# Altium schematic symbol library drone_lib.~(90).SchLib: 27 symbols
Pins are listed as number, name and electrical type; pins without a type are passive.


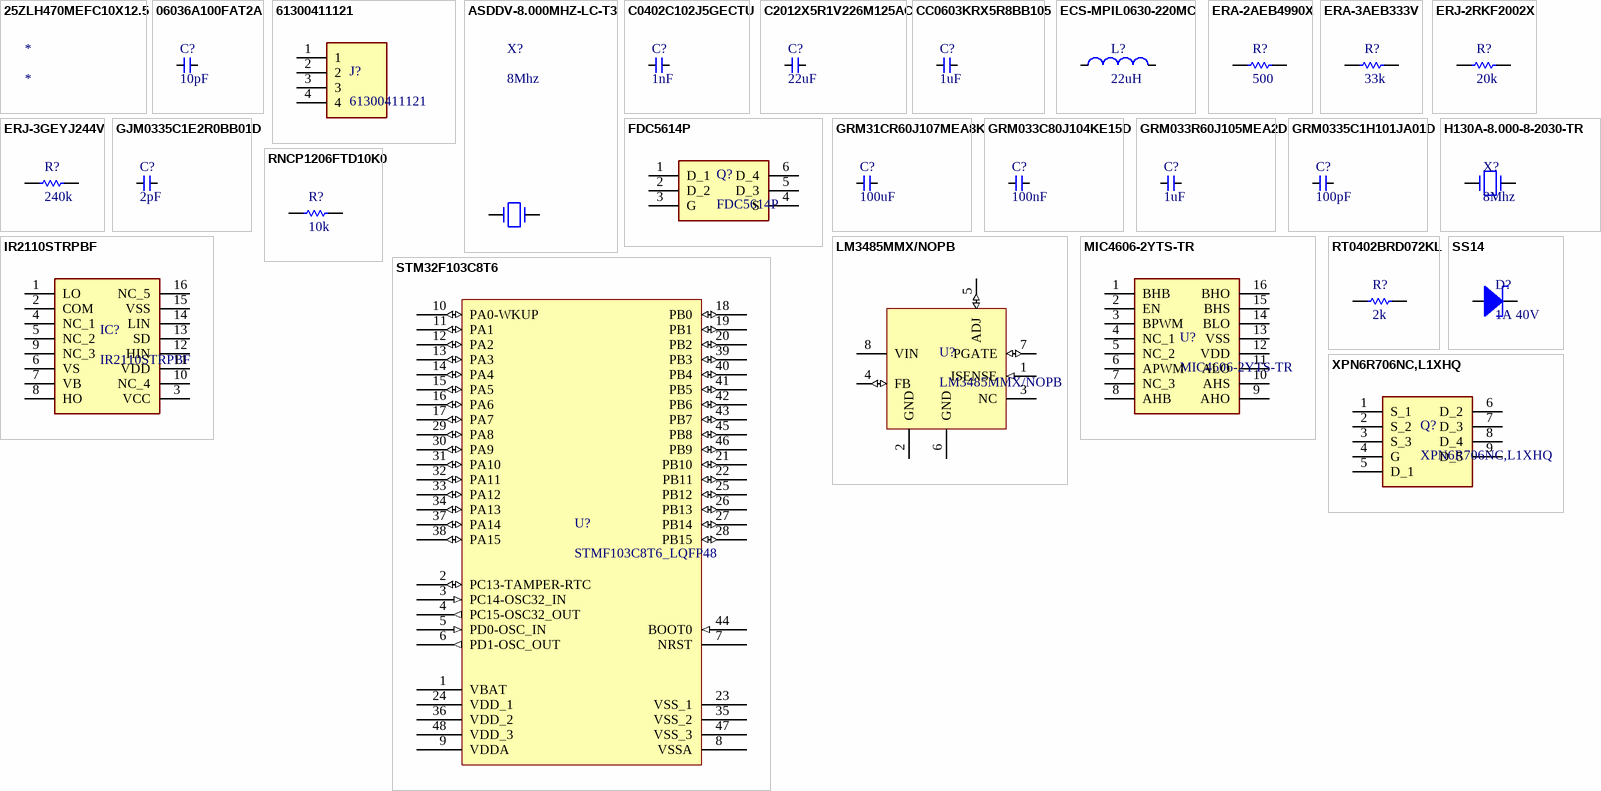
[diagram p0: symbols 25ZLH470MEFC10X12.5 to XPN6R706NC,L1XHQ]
## 25ZLH470MEFC10X12.5
designator *
Aluminum Electrolytic Capacitor, Polarized, Aluminum (wet), 25V, 20% +Tol, 20% -Tol, 470uF, Through Hole Mount; Manufacturer: Rubycon; Manufacturer Part Number: 25ZLH470MEFC10X12.5; Dielectric Material: Aluminium; Leakage Current: 117.5uA; Ripple Current: 731.5mA; Tan Delta: 0.14

## 06036A100FAT2A
designator C?, comment 10pF
Ceramic Capacitor, Ceramic, 6.3V, 1% +Tol, 1% -Tol, C0G, -/+30ppm/Cel TC, 0.00001uF, Surface Mount, 0603; Manufacturer: Kyocera AVX; Manufacturer Part Number: 06036A100FAT2A; Multilayer: No
pins: 1, 2

## 61300411121
designator J?
pins: 1, 2, 3, 4

## ASDDV-8.000MHZ-LC-T3
designator X?, comment 8Mhz
Osc, 8MHZ, Cmos/hcmos/lvcmos, SMD Rohs Compliant: Yes; Manufacturer: Abracon; Manufacturer Part Number: ASDDV-8.000MHZ-LC-T3
pins: 1, 2

## C0402C102J5GECTU
designator C?, comment 1nF
Ceramic Capacitor, Multilayer, Ceramic, 50V, 5% +Tol, 5% -Tol, C0G, -/+30ppm/Cel TC, 0.001uF, Surface Mount, 0402; Manufacturer: KEMET; Manufacturer Part Number: C0402C102J5GECTU
footprint C0402C104J4RACTU
pins: 1, 2

## C2012X5R1V226M125AC
designator C?, comment 22uF
Ceramic Capacitor, Multilayer, Ceramic, 35V, 20% +Tol, 20% -Tol, X5R, 15% TC, 22uF, Surface Mount, 0805; Manufacturer: TDK; Manufacturer Part Number: C2012X5R1V226M125AC; Multilayer: Yes
footprint CAPC2012X145N
pins: 1, 2

## CC0603KRX5R8BB105
designator C?, comment 1uF
Ceramic Capacitor, Multilayer, Ceramic, 25V, 10% +Tol, 10% -Tol, X5R, 15% TC, 1uF, Surface Mount, 0603; Manufacturer: Yageo; Manufacturer Part Number: CC0603KRX5R8BB105; Multilayer: Yes
footprint CAPC1608X90N
pins: 1, 2

## ECS-MPIL0630-220MC
designator L?, comment 22uH
General Purpose Inductor, 22uH, 20%, 1 Element, Ferrite-Core, SMD, 2826; Manufacturer: ECS International; Manufacturer Part Number: ECS-MPIL0630-220MC
footprint INDPM7166X300N
pins: 1, 2

## ERA-2AEB4990X
designator R?, comment 500
Fixed Resistor, Thin Film, 0.063W, 499ohm, 50V, 0.1% +/-Tol, 25ppm/Cel, Surface Mount, 0402; Manufacturer: Panasonic; Manufacturer Part Number: ERA-2AEB4990X; Power: 63mW; Rated Temperature: 85°C; Value: 499R; Working Voltage: 25V; Temperature Coefficient (ppm/Cel): 25; Package Height: 0.35mm; Package Length: 1mm; Package Width: 0.5mm; Reference Standard: AEC-Q200
footprint ERA2AED122X
pins: 2, 4

## ERA-3AEB333V
designator R?, comment 33k
Fixed Resistor, Thin Film, 0.1W, 33000ohm, 75V, 0.1% +/-Tol, 25ppm/Cel, Surface Mount, 0603; Manufacturer: Panasonic; Manufacturer Part Number: ERA-3AEB333V; Power: 100mW; Rated Temperature: 85°C; Value: 33kR; Temperature Coefficient (ppm/Cel): 25; Package Height: 0.45mm; Package Length: 1.6mm; Package Width: 0.8mm; Reference Standard: AEC-Q200
footprint ERA3AEB101V
pins: 2, 4

## ERJ-2RKF2002X
designator R?, comment 20k
Fixed Resistor, Metal Glaze/thick Film, 0.1W, 20000ohm, 50V, 1% +/-Tol, 100ppm/Cel, Surface Mount, 0402; Manufacturer: Panasonic; Manufacturer Part Number: ERJ-2RKF2002X; Power: 100mW; Rated Temperature: 70°C; Value: 20kR; Temperature Coefficient (ppm/Cel): 100; Package Height: 0.35mm; Package Length: 1mm; Package Width: 0.5mm; Reference Standard: AEC-Q200
footprint ERJ2RKD1004X
pins: 2, 4

## ERJ-3GEYJ244V
designator R?, comment 240k
Fixed Resistor, Metal Glaze/thick Film, 0.1W, 240000ohm, 75V, 5% +/-Tol, 200ppm/Cel, Surface Mount, 0603; Manufacturer: Panasonic; Manufacturer Part Number: ERJ-3GEYJ244V; Power: 100mW; Rated Temperature: 70°C; Value: 240kR; Temperature Coefficient (ppm/Cel): 200; Package Height: 0.45mm; Package Length: 1.6mm; Package Width: 0.8mm; Reference Standard: AEC-Q200
footprint ERJ3EKF1000V
pins: 2, 4

## FDC5614P
designator Q?
Small Signal Field-Effect Transistor, 3A I(D), 60V, 1-Element, P-Channel, Silicon, Metal-oxide Semiconductor FET; Manufacturer: ON Semiconductor / Fairchild; Package Body Material: Plastic; Drain-source On Resistance-Max: 105mR; Number of Elements: 1; Operating Mode: ENHANCEMENT MODE; Power Dissipation-Max (Abs): 1.6W; Transistor Application: SWITCHING; Qualification Status: Not Qualified
footprint SOT95P280X110-6N
pins: 1 D_1, 2 D_2, 3 G, 4 S, 5 D_3, 6 D_4

## GJM0335C1E2R0BB01D
designator C?, comment 2pF
Ceramic Capacitor, Multilayer, Ceramic, 25V, 5% +Tol, 5% -Tol, C0G, 30ppm/Cel TC, 0.000002uF, Surface Mount, 0201; Manufacturer: Murata; Manufacturer Part Number: GJM0335C1E2R0BB01D; Multilayer: Yes
footprint GJM033
pins: 1, 2

## GRM31CR60J107MEA8K
designator C?, comment 100uF
Ceramic Capacitor, Multilayer, Ceramic, 6.3V, 20% +Tol, 20% -Tol, X5R, 15% TC, 100uF, Surface Mount, 1206; Manufacturer: Murata; Manufacturer Part Number: GRM31CR60J107MEA8K
footprint GRM31x
pins: 1, 2

## GRM033C80J104KE15D
designator C?, comment 100nF
Ceramic Capacitor, Multilayer, Ceramic, 6.3V, 10% +Tol, 10% -Tol, X6S, 22% TC, 0.1uF, Surface Mount, 0201; Manufacturer: Murata; Manufacturer Part Number: GRM033C80J104KE15D; Multilayer: Yes
footprint GRM033D70J224ME01D
pins: 1, 2

## GRM033R60J105MEA2D
designator C?, comment 1uF
Ceramic Capacitor, Multilayer, Ceramic, 6.3V, 20% +Tol, 20% -Tol, X5R, 15% TC, 1uF, Surface Mount, 0201; Manufacturer: Murata; Manufacturer Part Number: GRM033R60J105MEA2D; Multilayer: Yes
footprint GRM033D70J224ME01D
pins: 1, 2

## GRM0335C1H101JA01D
designator C?, comment 100pF
Ceramic Capacitor, Multilayer, Ceramic, 50V, 5% +Tol, 5% -Tol, C0G, 30ppm/Cel TC, 0.0001uF, Surface Mount, 0201; Manufacturer: Murata; Manufacturer Part Number: GRM0335C1H101JA01D; Multilayer: Yes
pins: 1, 2

## H130A-8.000-8-2030-TR
designator X?, comment 8Mhz
Parallel - Fundamental Quartz Crystal, 8MHz Min, 150MHz Max, 8MHz Nom; Manufacturer: Raltron Electronics; Manufacturer Part Number: H130A-8.000-8-2030-TR
footprint 8Mhz Crystal
pins: 1, 2

## IR2110STRPBF
designator IC?
Half Bridge Based MOSFET Driver, 2.5A, CMOS, PDSO16; Manufacturer: Infineon; Package Body Material: Plastic; High Side Driver: Yes; Channels: 1; Supply Voltage1-Max: 520V; Supply Voltage1-Min: 6V; Max Supply Voltage: 20V; Min Supply Voltage: 3.3V; Nominal Supply Voltage: 15V; Turn-Off Delay Time: 0.125us; Turn-On Delay Time: 0.15us; Package Equivalence Code: SOP16,.4; Time @ Peak Reflow Temperature-Max (s): 30s; Qualification Status: Not Qualified
footprint SOIC127P1032X265-16N
pins: 1 LO, 2 COM, 3 VCC, 4 NC_1, 5 NC_2, 6 VS, 7 VB, 8 HO, 9 NC_3, 10 NC_4, 11 VDD, 12 HIN, 13 SD, 14 LIN, 15 VSS, 16 NC_5

## LM3485MMX/NOPB
designator U?
Switching Controller, Voltage-mode, 0.1A, 1000kHz Switching Freq-Max, PDSO8; Manufacturer: TI National Semiconductor; Package Body Material: Plastic; Control Technique: HYSTERETIC CURRENT MODE; Max Supply Voltage: 35V; Min Input Voltage: 4.5V; Nominal Supply Voltage: 12V; Channels: 1; Max Output current: 100mA; Package Equivalence Code: TSSOP8,.19; Switcher Configuration: SINGLE; Frequency: 1MHz; Time @ Peak Reflow Temperature-Max (s): 40s; Qualification Status: Not Qualified
footprint SOP65P490X110-8N
pins: 1 ISENSE (in), 2 GND (power), 3 NC (power), 4 FB (io), 5 ADJ (io), 6 GND (power), 7 PGATE (io), 8 VIN (power)

## MIC4606-2YTS-TR
designator U?
Full Bridge Based MOSFET Driver, 1A, PDSO16; Manufacturer: Microchip
footprint SOP65P640X120-16N
pins: 1 BHB, 2 EN, 3 BPWM, 4 NC_1, 5 NC_2, 6 APWM, 7 NC_3, 8 AHB, 9 AHO, 10 AHS, 11 ALO, 12 VDD, 13 VSS, 14 BLO, 15 BHS, 16 BHO

## RNCP1206FTD10K0
designator R?, comment 10k
Fixed Resistor, Thin Film, 0.5W, 10000ohm, 200V, 1% +/-Tol, 100ppm/Cel, Surface Mount, 1206; Manufacturer: Stackpole Electronics; Manufacturer Part Number: RNCP1206FTD10K0; Additional Feature: ANTI-SULFUR; Power: 500mW; Rated Temperature: 70°C; Value: 10kR; Temperature Coefficient (ppm/Cel): 100; Package Height: 0.5mm; Package Length: 3.1mm; Package Width: 1.5mm
footprint RESC3115X60N
pins: 2, 4

## RT0402BRD072KL
designator R?, comment 2k
Fixed Resistor, Thin Film, 0.0625W, 2000ohm, 50V, 0.1% +/-Tol, 25ppm/Cel, Surface Mount, 0402; Manufacturer: Yageo; Manufacturer Part Number: RT0402BRD072KL; Additional Feature: HIGH PRECISION; Power: 62.5mW; Rated Temperature: 70°C; Temperature Coefficient (ppm/Cel): 25; Package Height: 0.3mm; Package Length: 1mm; Package Width: 0.5mm
pins: 2, 4

## SS14
designator D?, comment 1A 40V
Rectifier Diode, Schottky, 1 Phase, 1 Element, 1A, 40V V(RRM), Silicon, DO-214AC; Manufacturer: ON Semiconductor / Fairchild; Manufacturer Part Number: SS14; Package Body Material: Plastic; Forward Voltage: 500mV; Non-rep Pk Forward Current-Max: 30A; Number of Elements: 1; Additional Feature: FREE WHEELING DIODE; Max Power Dissipation: 1.1W; Qualification Status: Not Qualified
footprint DIOM5026X262N
pins: +, -

## STM32F103C8T6
designator U?, comment STMF103C8T6_LQFP48
ARM Cortex-M3 STM32 F1 Microcontroller 32-Bit 72MHz 64kB FLASH LQFP48 STM32F103C8T6; Manufacturer: STMicroelectronics; Package Body Material: Plastic; Clock Frequency: 16MHz; Number of I/O Lines: 37; Package Equivalence Code: QFP48,.35SQ,20; Power Supplies: 2.5/3.3; Max Supply Current: 50mA; Max Supply Voltage: 3.6V; Min Supply Voltage: 2V; Nominal Supply Voltage: 3.3V; Time @ Peak Reflow Temperature-Max (s): 30s; Peripherals: POR; Interface: I2C; Qualification Status: Not Qualified
footprint STM32F103C8T6_LQFP48
pins: 1 VBAT (power), 2 PC13-TAMPER-RTC (io), 3 PC14-OSC32_IN (in), 4 PC15-OSC32_OUT (out), 5 PD0-OSC_IN (in), 6 PD1-OSC_OUT (out), 7 NRST, 8 VSSA (power), 9 VDDA (power), 10 PA0-WKUP (io), 11 PA1 (io), 12 PA2 (io), 13 PA3 (io), 14 PA4 (io), 15 PA5 (io), 16 PA6 (io), 17 PA7 (io), 18 PB0 (io), 19 PB1 (io), 20 PB2 (io), 21 PB10 (io), 22 PB11 (io), 23 VSS_1 (power), 24 VDD_1 (power), 25 PB12 (io), 26 PB13 (io), 27 PB14 (io), 28 PB15 (io), 29 PA8 (io), 30 PA9 (io), 31 PA10 (io), 32 PA11 (io), 33 PA12 (io), 34 PA13 (io), 35 VSS_2 (power), 36 VDD_2 (power), 37 PA14 (io), 38 PA15 (io), 39 PB3 (io), 40 PB4 (io), 41 PB5 (io), 42 PB6 (io), 43 PB7 (io), 44 BOOT0 (in), 45 PB8 (io), 46 PB9 (io), 47 VSS_3 (power), 48 VDD_3 (power)

## XPN6R706NC,L1XHQ
designator Q?
Mosfet N-ch 60V 40A 8TSON; Manufacturer: Toshiba
footprint XPN6R706NCL1XHQ
pins: 1 S_1, 2 S_2, 3 S_3, 4 G, 5 D_1, 6 D_2, 7 D_3, 8 D_4, 9 D_5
